VERSION 5.7 ;
  NOWIREEXTENSIONATPIN ON ;
  DIVIDERCHAR "/" ;
  BUSBITCHARS "[]" ;
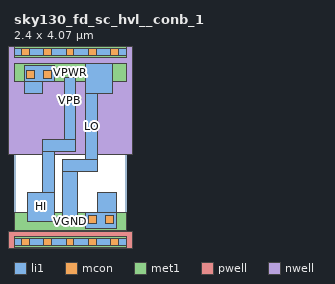
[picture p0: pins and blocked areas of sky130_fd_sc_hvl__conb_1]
MACRO sky130_fd_sc_hvl__conb_1
  CLASS BLOCK ;
  FOREIGN sky130_fd_sc_hvl__conb_1 ;
  ORIGIN 0.000 0.000 ;
  SIZE 2.400 BY 4.070 ;
  PIN VGND
    USE GROUND ;
    PORT
      LAYER li1 ;
        RECT 1.780 0.625 2.185 1.070 ;
        RECT 1.535 0.285 2.185 0.625 ;
      LAYER mcon ;
        RECT 1.595 0.395 1.765 0.565 ;
        RECT 1.955 0.395 2.125 0.565 ;
      LAYER met1 ;
        RECT 0.000 0.255 2.400 0.625 ;
    END
  END VGND
  PIN VNB
    ANTENNADIFFAREA 0.408000 ;
    PORT
      LAYER pwell ;
        RECT -0.130 -0.215 2.530 0.215 ;
      LAYER li1 ;
        RECT 0.000 -0.085 2.400 0.085 ;
      LAYER mcon ;
        RECT 0.155 -0.085 0.325 0.085 ;
        RECT 0.635 -0.085 0.805 0.085 ;
        RECT 1.115 -0.085 1.285 0.085 ;
        RECT 1.595 -0.085 1.765 0.085 ;
        RECT 2.075 -0.085 2.245 0.085 ;
      LAYER met1 ;
        RECT 0.000 -0.115 2.400 0.115 ;
    END
  END VNB
  PIN VPB
    ANTENNADIFFAREA 0.408000 ;
    PORT
      LAYER nwell ;
        RECT -0.330 1.885 2.730 4.485 ;
      LAYER li1 ;
        RECT 0.000 3.985 2.400 4.155 ;
      LAYER mcon ;
        RECT 0.155 3.985 0.325 4.155 ;
        RECT 0.635 3.985 0.805 4.155 ;
        RECT 1.115 3.985 1.285 4.155 ;
        RECT 1.595 3.985 1.765 4.155 ;
        RECT 2.075 3.985 2.245 4.155 ;
      LAYER met1 ;
        RECT 0.000 3.955 2.400 4.185 ;
    END
  END VPB
  PIN VPWR
    USE POWER ;
    PORT
      LAYER li1 ;
        RECT 0.215 3.445 0.865 3.785 ;
        RECT 0.215 3.175 0.620 3.445 ;
      LAYER mcon ;
        RECT 0.275 3.505 0.445 3.675 ;
        RECT 0.635 3.505 0.805 3.675 ;
      LAYER met1 ;
        RECT 0.000 3.445 2.400 3.815 ;
    END
  END VPWR
  PIN HI
    PORT
      LAYER li1 ;
        RECT 1.075 2.185 1.325 3.530 ;
        RECT 0.615 1.935 1.325 2.185 ;
        RECT 0.615 1.070 0.865 1.935 ;
        RECT 0.290 0.430 0.865 1.070 ;
    END
  END HI
  PIN LO
    PORT
      LAYER li1 ;
        RECT 1.530 3.175 2.110 3.815 ;
        RECT 1.530 1.765 1.795 3.175 ;
        RECT 1.035 1.500 1.795 1.765 ;
        RECT 1.035 0.500 1.365 1.500 ;
    END
  END LO
END sky130_fd_sc_hvl__conb_1
END LIBRARY

